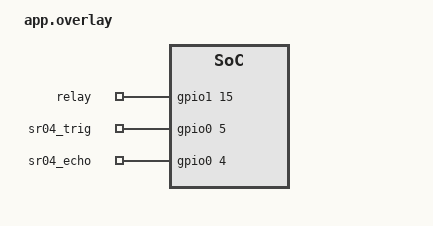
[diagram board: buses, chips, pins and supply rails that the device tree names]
/ {
    aliases {
        relay = &relay;
        sr04-trig = &sr04_trig;
        sr04-echo = &sr04_echo;
    };

    relays {
        compatible = "gpio-leds";

        relay: relay {
            gpios = <&gpio1 15 GPIO_ACTIVE_HIGH>;
        };
    };

    sr04_pins {
        compatible = "gpio-keys";
        sr04_trig: sr04_trig {
            gpios = <&gpio0 5 GPIO_ACTIVE_HIGH>;
        };
        sr04_echo: sr04_echo {
            gpios = <&gpio0 4 GPIO_ACTIVE_HIGH>;
        };
    };
};
